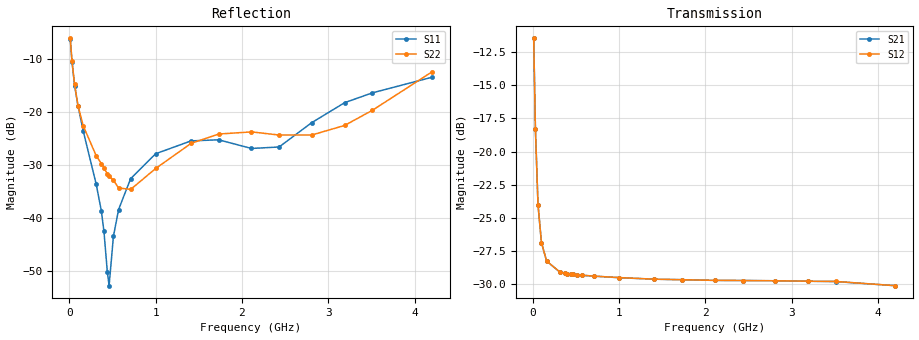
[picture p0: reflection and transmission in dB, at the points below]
! Integrated Device Technology
! Corporate Headquarters
! 6024 Silver Creek Valley Road
! San Jose, CA 95138  USA
! Phone:  1-408-284-8200
! Toll Free:  1-800-223-1366
! Webpage:  http://www.idt.com/
! Timing and RF Division
! 515 Groton Road, Suite 102
! Westford, MA 01886-6024
! Device:  F1950
! Description: 7-bit 0.25 dB Digital Step Attenuator
! Frequency:  150.0 -  4000.00 MHz
! Package:  4x4 mm Thin QFN Plastic Package: 24 pin
! Ports:  2 RF, 12 DC
!  Pin  1  = D0
!  Pin  2  = VDD
!  Pin  3  = Vmode
!  Pin  4  = GND
!  Pin  5  = RF1  =  Port 1
!  Pin  6  = GND
!  Pin  7  = GND
!  Pin  8  = GND
!  Pin  9  = GND
!  Pin 10  = GND
!  Pin 11  = GND
!  Pin 12  = GND
!  Pin 13  = GND
!  Pin 14  = RF2  =  Port 2
!  Pin 15  = GND
!  Pin 16  = LE
!  Pin 17  = CLK
!  Pin 18  = DATE
!  Pin 19  = D6
!  Pin 20  = D5
!  Pin 21  = D4
!  Pin 22  = D3
!  Pin 23  = D2
!  Pin 24  = D1
! State:  114
! Atten State:  28.50 dB
! Voltage:  +5.00 Volts
! Current:  Not Measured mA
! Data:  The device was measured on a the F195X evaluation board which has
!  individual transmission lines to the RF pins.  Data was collected
!  using a calibrated network analyzer.  The evaluation board was
!  de-embedded using a TRL calibration technique.
!  The reference plane is the edge of the package pin.
! Misc:  Board 2019
!  Action Tracker AT0250
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# GHz S dB R 50
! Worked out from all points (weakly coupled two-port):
!   420 points, 10 MHz to 4.2 GHz, reference 50 ohm
!   highest |S21| = -11.47 dB at 10 MHz (marker M1); lowest = -30.1 dB at 4.2 GHz (marker M2)
!   lowest |S11| = -52.7 dB at 460 MHz (marker M3), VSWR 1.00, Z = 49.8 - j0.0609 ohm
!   |S11| at or under -10 dB: 27.22 MHz to end of sweep
!   |S22| runs from -34.9 to -6.1 dB; largest |S21 - S12| = 7.1e-05
!   S11 on the Smith chart (normalised r, x): 10 MHz: 2.02, -1.20; 30 MHz: 1.27, -0.65; 60 MHz: 1.10, -0.36; 370 MHz: 1.01, -0.02; 4.2 GHz: 0.68, +0.17
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0.01  -6.29 -27.9  -11.47 -38.7  -11.47 -38.7  -6.13 -29.0
0.03  -10.55 -51.5  -18.30 -61.3  -18.30 -61.3  -10.44 -53.3
0.06  -15.01 -64.1  -23.99 -55.2  -23.99 -55.2  -14.78 -65.9
0.1  -18.89 -70.9  -26.85 -41.7  -26.85 -41.7  -18.86 -71.4
0.16  -23.58 -73.0  -28.24 -29.7  -28.24 -29.7  -22.59 -76.6
0.31  -33.56 -73.9  -29.05 -18.5  -29.04 -18.5  -28.23 -84.7
0.37  -38.62 -73.2  -29.15 -16.7  -29.15 -16.7  -29.71 -87.5
0.4  -42.47 -80.2  -29.18 -16.1  -29.18 -16.1  -30.55 -89.1
0.44  -50.20 -111.2  -29.22 -15.4  -29.22 -15.4  -31.66 -94.0
0.46  -52.72 -164.7  -29.24 -15.1  -29.24 -15.1  -32.05 -97.5
0.51  -43.44 144.4  -29.27 -14.6  -29.28 -14.6  -32.86 -103.4
0.57  -38.37 137.2  -29.31 -14.3  -29.30 -14.2  -34.32 -114.3
0.71  -32.55 138.9  -29.37 -13.9  -29.37 -13.9  -34.58 -142.0
1  -27.86 148.1  -29.49 -14.7  -29.48 -14.7  -30.64 178.3
1.41  -25.44 162.6  -29.60 -16.7  -29.60 -16.7  -25.91 160.1
1.73  -25.24 167.8  -29.64 -18.5  -29.64 -18.6  -24.15 151.7
2.11  -26.87 157.3  -29.69 -21.5  -29.69 -21.6  -23.75 141.9
2.43  -26.59 126.2  -29.70 -23.5  -29.70 -23.5  -24.34 131.1
2.81  -21.99 105.4  -29.72 -26.7  -29.72 -26.7  -24.33 115.8
3.19  -18.24 108.6  -29.76 -29.7  -29.75 -29.8  -22.53 110.2
3.51  -16.40 117.3  -29.78 -31.9  -29.77 -32.0  -19.69 113.0
4.2  -13.46 145.5  -30.09 -34.6  -30.09 -34.7  -12.46 127.0
